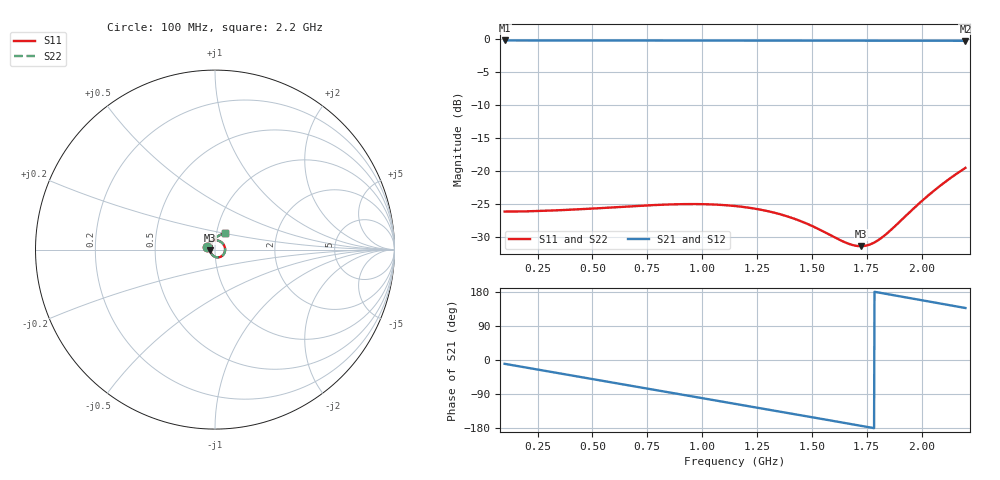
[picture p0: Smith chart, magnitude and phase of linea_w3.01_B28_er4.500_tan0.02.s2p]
! Chirptenna · simulación 3D de una microstrip de dos puertos (S12 = S21, S22 = S11 por simetría)
# HZ S RI R 50
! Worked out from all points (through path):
!   1101 points, 100 MHz to 2.2 GHz, reference 50 ohm
!   highest |S21| = -0.15 dB at 100 MHz (marker M1); lowest = -0.2 dB at 2.2 GHz (marker M2)
!   group delay of S21, straight-line fit = 281 ps
!   lowest |S11| = -31.4 dB at 1.723 GHz (marker M3), VSWR 1.06, Z = 47.4 - j0.454 ohm
!   |S11| at or under -10 dB: start of sweep to end of sweep
!   |S22| runs from -31.4 to -19.5 dB; largest |S21 - S12| = 0
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1e8  -0.0467 0.0164  0.968 -0.1715  0.968 -0.1715  -0.0467 0.0164
1.820909e8  -0.0403 0.0289  0.9333 -0.3084  0.9333 -0.3084  -0.0403 0.0289
2.699091e8  -0.0303 0.04  0.8748 -0.4478  0.8748 -0.4478  -0.0303 0.04
3.596364e8  -0.0171 0.0478  0.7938 -0.5791  0.7938 -0.5791  -0.0171 0.0478
4.512727e8  -0.00189 0.0516  0.6908 -0.6984  0.6908 -0.6984  -0.00189 0.0516
6.307273e8  0.0281 0.0458  0.4406 -0.8774  0.4406 -0.8774  0.0281 0.0458
7.166364e8  0.0401 0.0373  0.3039 -0.9333  0.3039 -0.9333  0.0401 0.0373
8.006364e8  0.0491 0.0262  0.1636 -0.9675  0.1636 -0.9675  0.0491 0.0262
8.884545e8  0.0548 0.0126  0.0132 -0.9809  0.0132 -0.9809  0.0548 0.0126
9.743636e8  0.0564 -0.0016  -0.1342 -0.9716  -0.1342 -0.9716  0.0564 -0.0016
1.062182e9  0.0537 -0.0157  -0.2818 -0.9393  -0.2818 -0.9393  0.0537 -0.0157
1.15e9  0.0468 -0.028  -0.4228 -0.8848  -0.4228 -0.8848  0.0468 -0.028
1.318e9  0.0249 -0.0423  -0.6623 -0.7233  -0.6623 -0.7233  0.0249 -0.0423
1.411545e9  0.01 -0.043  -0.7723 -0.6048  -0.7723 -0.6048  0.01 -0.043
1.501273e9  -0.004 -0.0383  -0.8584 -0.4752  -0.8584 -0.4752  -0.004 -0.0383
1.654e9  -0.0224 -0.0181  -0.9547 -0.2281  -0.9547 -0.2281  -0.0224 -0.0181
1.722727e9  -0.0266 -0.00479  -0.9755 -0.1097  -0.9755 -0.1097  -0.0266 -0.00479
1.781909e9  -0.0275 0.00816  -0.9816 -0.00621  -0.9816 -0.00621  -0.0275 0.00816
1.850636e9  -0.0248 0.0243  -0.9748 0.1143  -0.9748 0.1143  -0.0248 0.0243
1.934636e9  -0.0156 0.0443  -0.9461 0.2594  -0.9461 0.2594  -0.0156 0.0443
2.018636e9  0.000264 0.063  -0.8954 0.3986  -0.8954 0.3986  0.000264 0.063
2.2e9  0.056 0.0902  -0.7164 0.6632  -0.7164 0.6632  0.056 0.0902
